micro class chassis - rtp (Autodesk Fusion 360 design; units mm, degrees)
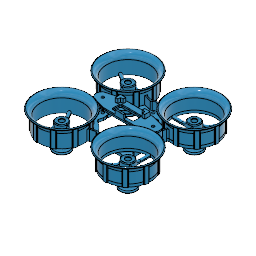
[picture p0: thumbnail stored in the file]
base_feature "Base Feature1"
base_feature "Base Feature1" bodies "Motor Guard", "Motor Guard (1)", "Motor Guard (2)", "Motor Guard (3)"
base_feature "Base Feature1" bodies "Landing Gear"
base_feature "Base Feature1" bodies "Cam Mount", "Cam Mount (1)"
ground "Ground1"
base_feature "Base Feature1" bodies "Main Chassis"
ground "Ground2"
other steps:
create_component "CreateComponent1"
create_component "CreateComponent2"
create_component "CreateComponent3"
create_component "CreateComponent4"
named bodies: "Cam Mount", "Main Chassis", "Motor Guard", "Motor Guard (1)", "Motor Guard (2)", "Motor Guard (3)", "Landing Gear", "Cam Mount (1)"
